VERSION 5.7 ;
  NOWIREEXTENSIONATPIN ON ;
  DIVIDERCHAR "/" ;
  BUSBITCHARS "[]" ;
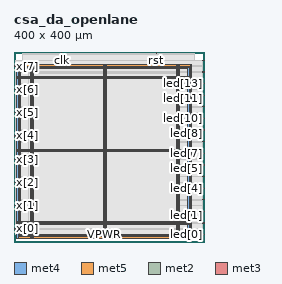
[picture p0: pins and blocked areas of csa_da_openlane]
MACRO csa_da_openlane
  CLASS BLOCK ;
  FOREIGN csa_da_openlane ;
  ORIGIN 0.000 0.000 ;
  SIZE 400.000 BY 400.000 ;
  PIN VGND
    DIRECTION INOUT ;
    USE GROUND ;
    PORT
      LAYER met4 ;
        RECT 6.240 7.760 9.240 373.040 ;
    END
    PORT
      LAYER met5 ;
        RECT 6.240 7.760 373.720 10.760 ;
    END
    PORT
      LAYER met5 ;
        RECT 6.240 370.040 373.720 373.040 ;
    END
    PORT
      LAYER met4 ;
        RECT 370.720 7.760 373.720 373.040 ;
    END
    PORT
      LAYER met4 ;
        RECT 39.060 7.760 40.660 373.040 ;
    END
    PORT
      LAYER met4 ;
        RECT 192.660 7.760 194.260 373.040 ;
    END
    PORT
      LAYER met4 ;
        RECT 346.260 7.760 347.860 373.040 ;
    END
    PORT
      LAYER met5 ;
        RECT 6.240 40.910 373.720 42.510 ;
    END
    PORT
      LAYER met5 ;
        RECT 6.240 194.090 373.720 195.690 ;
    END
    PORT
      LAYER met5 ;
        RECT 6.240 347.270 373.720 348.870 ;
    END
  END VGND
  PIN VPWR
    DIRECTION INOUT ;
    USE POWER ;
    PORT
      LAYER met4 ;
        RECT 11.240 12.760 14.240 368.040 ;
    END
    PORT
      LAYER met5 ;
        RECT 11.240 12.760 368.720 15.760 ;
    END
    PORT
      LAYER met5 ;
        RECT 11.240 365.040 368.720 368.040 ;
    END
    PORT
      LAYER met4 ;
        RECT 365.720 12.760 368.720 368.040 ;
    END
    PORT
      LAYER met4 ;
        RECT 35.760 7.760 37.360 373.040 ;
    END
    PORT
      LAYER met4 ;
        RECT 189.360 7.760 190.960 373.040 ;
    END
    PORT
      LAYER met4 ;
        RECT 342.960 7.760 344.560 373.040 ;
    END
    PORT
      LAYER met5 ;
        RECT 6.240 37.610 373.720 39.210 ;
    END
    PORT
      LAYER met5 ;
        RECT 6.240 190.790 373.720 192.390 ;
    END
    PORT
      LAYER met5 ;
        RECT 6.240 343.970 373.720 345.570 ;
    END
  END VPWR
  PIN clk
    DIRECTION INPUT ;
    USE SIGNAL ;
    ANTENNAGATEAREA 0.852000 ;
    PORT
      LAYER met2 ;
        RECT 99.910 396.000 100.190 400.000 ;
    END
  END clk
  PIN led[0]
    DIRECTION OUTPUT TRISTATE ;
    USE SIGNAL ;
    ANTENNADIFFAREA 0.795200 ;
    PORT
      LAYER met3 ;
        RECT 396.000 15.000 400.000 15.600 ;
    END
  END led[0]
  PIN led[10]
    DIRECTION OUTPUT TRISTATE ;
    USE SIGNAL ;
    ANTENNADIFFAREA 0.795200 ;
    PORT
      LAYER met3 ;
        RECT 396.000 259.800 400.000 260.400 ;
    END
  END led[10]
  PIN led[11]
    DIRECTION OUTPUT TRISTATE ;
    USE SIGNAL ;
    ANTENNADIFFAREA 0.795200 ;
    PORT
      LAYER met3 ;
        RECT 396.000 284.280 400.000 284.880 ;
    END
  END led[11]
  PIN led[12]
    DIRECTION OUTPUT TRISTATE ;
    USE SIGNAL ;
    ANTENNADIFFAREA 0.795200 ;
    PORT
      LAYER met3 ;
        RECT 396.000 308.760 400.000 309.360 ;
    END
  END led[12]
  PIN led[13]
    DIRECTION OUTPUT TRISTATE ;
    USE SIGNAL ;
    ANTENNADIFFAREA 0.795200 ;
    PORT
      LAYER met3 ;
        RECT 396.000 333.240 400.000 333.840 ;
    END
  END led[13]
  PIN led[14]
    DIRECTION OUTPUT TRISTATE ;
    USE SIGNAL ;
    ANTENNADIFFAREA 0.795200 ;
    PORT
      LAYER met3 ;
        RECT 396.000 357.720 400.000 358.320 ;
    END
  END led[14]
  PIN led[15]
    DIRECTION OUTPUT TRISTATE ;
    USE SIGNAL ;
    ANTENNADIFFAREA 0.795200 ;
    PORT
      LAYER met3 ;
        RECT 396.000 382.200 400.000 382.800 ;
    END
  END led[15]
  PIN led[1]
    DIRECTION OUTPUT TRISTATE ;
    USE SIGNAL ;
    ANTENNADIFFAREA 0.795200 ;
    PORT
      LAYER met3 ;
        RECT 396.000 39.480 400.000 40.080 ;
    END
  END led[1]
  PIN led[2]
    DIRECTION OUTPUT TRISTATE ;
    USE SIGNAL ;
    ANTENNADIFFAREA 0.795200 ;
    PORT
      LAYER met3 ;
        RECT 396.000 63.960 400.000 64.560 ;
    END
  END led[2]
  PIN led[3]
    DIRECTION OUTPUT TRISTATE ;
    USE SIGNAL ;
    ANTENNADIFFAREA 0.795200 ;
    PORT
      LAYER met3 ;
        RECT 396.000 88.440 400.000 89.040 ;
    END
  END led[3]
  PIN led[4]
    DIRECTION OUTPUT TRISTATE ;
    USE SIGNAL ;
    ANTENNADIFFAREA 0.795200 ;
    PORT
      LAYER met3 ;
        RECT 396.000 112.920 400.000 113.520 ;
    END
  END led[4]
  PIN led[5]
    DIRECTION OUTPUT TRISTATE ;
    USE SIGNAL ;
    ANTENNADIFFAREA 0.795200 ;
    PORT
      LAYER met3 ;
        RECT 396.000 137.400 400.000 138.000 ;
    END
  END led[5]
  PIN led[6]
    DIRECTION OUTPUT TRISTATE ;
    USE SIGNAL ;
    ANTENNADIFFAREA 0.795200 ;
    PORT
      LAYER met3 ;
        RECT 396.000 161.880 400.000 162.480 ;
    END
  END led[6]
  PIN led[7]
    DIRECTION OUTPUT TRISTATE ;
    USE SIGNAL ;
    ANTENNADIFFAREA 0.795200 ;
    PORT
      LAYER met3 ;
        RECT 396.000 186.360 400.000 186.960 ;
    END
  END led[7]
  PIN led[8]
    DIRECTION OUTPUT TRISTATE ;
    USE SIGNAL ;
    ANTENNADIFFAREA 0.795200 ;
    PORT
      LAYER met3 ;
        RECT 396.000 210.840 400.000 211.440 ;
    END
  END led[8]
  PIN led[9]
    DIRECTION OUTPUT TRISTATE ;
    USE SIGNAL ;
    ANTENNADIFFAREA 0.795200 ;
    PORT
      LAYER met3 ;
        RECT 396.000 235.320 400.000 235.920 ;
    END
  END led[9]
  PIN rst
    DIRECTION INPUT ;
    USE SIGNAL ;
    ANTENNAGATEAREA 0.196500 ;
    PORT
      LAYER met2 ;
        RECT 299.550 396.000 299.830 400.000 ;
    END
  END rst
  PIN x[0]
    DIRECTION INPUT ;
    USE SIGNAL ;
    ANTENNAGATEAREA 0.213000 ;
    PORT
      LAYER met3 ;
        RECT 0.000 27.240 4.000 27.840 ;
    END
  END x[0]
  PIN x[1]
    DIRECTION INPUT ;
    USE SIGNAL ;
    ANTENNAGATEAREA 0.196500 ;
    PORT
      LAYER met3 ;
        RECT 0.000 76.200 4.000 76.800 ;
    END
  END x[1]
  PIN x[2]
    DIRECTION INPUT ;
    USE SIGNAL ;
    ANTENNAGATEAREA 0.196500 ;
    PORT
      LAYER met3 ;
        RECT 0.000 125.160 4.000 125.760 ;
    END
  END x[2]
  PIN x[3]
    DIRECTION INPUT ;
    USE SIGNAL ;
    ANTENNAGATEAREA 0.196500 ;
    PORT
      LAYER met3 ;
        RECT 0.000 174.120 4.000 174.720 ;
    END
  END x[3]
  PIN x[4]
    DIRECTION INPUT ;
    USE SIGNAL ;
    ANTENNAGATEAREA 0.196500 ;
    PORT
      LAYER met3 ;
        RECT 0.000 223.080 4.000 223.680 ;
    END
  END x[4]
  PIN x[5]
    DIRECTION INPUT ;
    USE SIGNAL ;
    ANTENNAGATEAREA 0.196500 ;
    PORT
      LAYER met3 ;
        RECT 0.000 272.040 4.000 272.640 ;
    END
  END x[5]
  PIN x[6]
    DIRECTION INPUT ;
    USE SIGNAL ;
    ANTENNAGATEAREA 0.196500 ;
    PORT
      LAYER met3 ;
        RECT 0.000 321.000 4.000 321.600 ;
    END
  END x[6]
  PIN x[7]
    DIRECTION INPUT ;
    USE SIGNAL ;
    ANTENNAGATEAREA 0.196500 ;
    PORT
      LAYER met3 ;
        RECT 0.000 369.960 4.000 370.560 ;
    END
  END x[7]
  OBS
      LAYER li1 ;
        RECT 20.240 21.675 359.720 359.125 ;
      LAYER met1 ;
        RECT 17.550 21.520 379.430 379.400 ;
      LAYER met2 ;
        RECT 17.570 395.720 99.630 396.000 ;
        RECT 100.470 395.720 299.270 396.000 ;
        RECT 300.110 395.720 379.410 396.000 ;
        RECT 17.570 15.115 379.410 395.720 ;
      LAYER met3 ;
        RECT 4.000 381.800 395.600 382.665 ;
        RECT 4.000 370.960 396.000 381.800 ;
        RECT 4.400 369.560 396.000 370.960 ;
        RECT 4.000 358.720 396.000 369.560 ;
        RECT 4.000 357.320 395.600 358.720 ;
        RECT 4.000 334.240 396.000 357.320 ;
        RECT 4.000 332.840 395.600 334.240 ;
        RECT 4.000 322.000 396.000 332.840 ;
        RECT 4.400 320.600 396.000 322.000 ;
        RECT 4.000 309.760 396.000 320.600 ;
        RECT 4.000 308.360 395.600 309.760 ;
        RECT 4.000 285.280 396.000 308.360 ;
        RECT 4.000 283.880 395.600 285.280 ;
        RECT 4.000 273.040 396.000 283.880 ;
        RECT 4.400 271.640 396.000 273.040 ;
        RECT 4.000 260.800 396.000 271.640 ;
        RECT 4.000 259.400 395.600 260.800 ;
        RECT 4.000 236.320 396.000 259.400 ;
        RECT 4.000 234.920 395.600 236.320 ;
        RECT 4.000 224.080 396.000 234.920 ;
        RECT 4.400 222.680 396.000 224.080 ;
        RECT 4.000 211.840 396.000 222.680 ;
        RECT 4.000 210.440 395.600 211.840 ;
        RECT 4.000 187.360 396.000 210.440 ;
        RECT 4.000 185.960 395.600 187.360 ;
        RECT 4.000 175.120 396.000 185.960 ;
        RECT 4.400 173.720 396.000 175.120 ;
        RECT 4.000 162.880 396.000 173.720 ;
        RECT 4.000 161.480 395.600 162.880 ;
        RECT 4.000 138.400 396.000 161.480 ;
        RECT 4.000 137.000 395.600 138.400 ;
        RECT 4.000 126.160 396.000 137.000 ;
        RECT 4.400 124.760 396.000 126.160 ;
        RECT 4.000 113.920 396.000 124.760 ;
        RECT 4.000 112.520 395.600 113.920 ;
        RECT 4.000 89.440 396.000 112.520 ;
        RECT 4.000 88.040 395.600 89.440 ;
        RECT 4.000 77.200 396.000 88.040 ;
        RECT 4.400 75.800 396.000 77.200 ;
        RECT 4.000 64.960 396.000 75.800 ;
        RECT 4.000 63.560 395.600 64.960 ;
        RECT 4.000 40.480 396.000 63.560 ;
        RECT 4.000 39.080 395.600 40.480 ;
        RECT 4.000 28.240 396.000 39.080 ;
        RECT 4.400 26.840 396.000 28.240 ;
        RECT 4.000 16.000 396.000 26.840 ;
        RECT 4.000 15.135 395.600 16.000 ;
      LAYER met4 ;
        RECT 29.735 40.975 35.360 354.785 ;
        RECT 37.760 40.975 38.660 354.785 ;
        RECT 41.060 40.975 188.960 354.785 ;
        RECT 191.360 40.975 192.260 354.785 ;
        RECT 194.660 40.975 342.560 354.785 ;
        RECT 344.960 40.975 345.860 354.785 ;
        RECT 348.260 40.975 349.305 354.785 ;
  END
END csa_da_openlane
END LIBRARY

